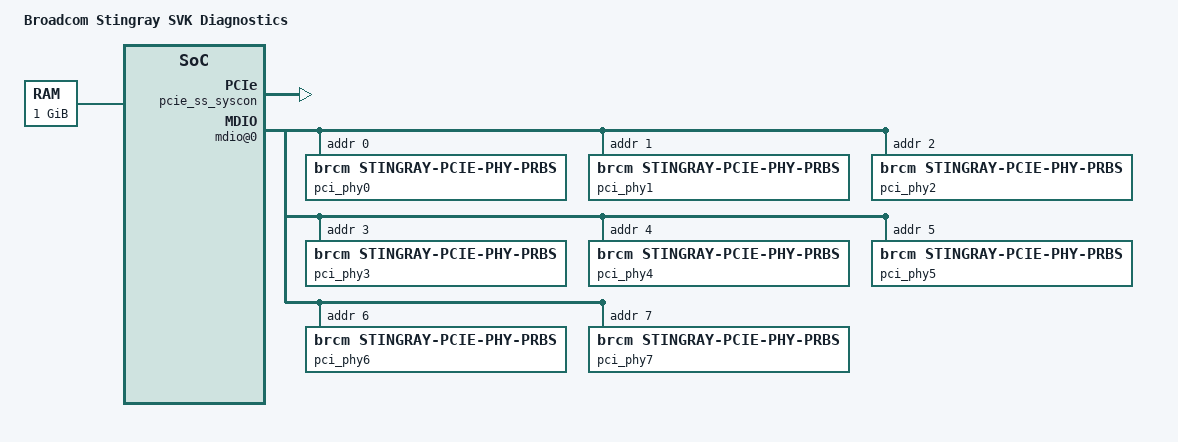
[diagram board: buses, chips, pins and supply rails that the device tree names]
/*
 *  BSD LICENSE
 *
 *  Copyright(c) 2016 Broadcom.  All rights reserved.
 *
 *  Redistribution and use in source and binary forms, with or without
 *  modification, are permitted provided that the following conditions
 *  are met:
 *
 *    * Redistributions of source code must retain the above copyright
 *      notice, this list of conditions and the following disclaimer.
 *    * Redistributions in binary form must reproduce the above copyright
 *      notice, this list of conditions and the following disclaimer in
 *      the documentation and/or other materials provided with the
 *      distribution.
 *    * Neither the name of Broadcom Corporation nor the names of its
 *      contributors may be used to endorse or promote products derived
 *      from this software without specific prior written permission.
 *
 *  THIS SOFTWARE IS PROVIDED BY THE COPYRIGHT HOLDERS AND CONTRIBUTORS
 *  "AS IS" AND ANY EXPRESS OR IMPLIED WARRANTIES, INCLUDING, BUT NOT
 *  LIMITED TO, THE IMPLIED WARRANTIES OF MERCHANTABILITY AND FITNESS FOR
 *  A PARTICULAR PURPOSE ARE DISCLAIMED. IN NO EVENT SHALL THE COPYRIGHT
 *  OWNER OR CONTRIBUTORS BE LIABLE FOR ANY DIRECT, INDIRECT, INCIDENTAL,
 *  SPECIAL, EXEMPLARY, OR CONSEQUENTIAL DAMAGES (INCLUDING, BUT NOT
 *  LIMITED TO, PROCUREMENT OF SUBSTITUTE GOODS OR SERVICES; LOSS OF USE,
 *  DATA, OR PROFITS; OR BUSINESS INTERRUPTION) HOWEVER CAUSED AND ON ANY
 *  THEORY OF LIABILITY, WHETHER IN CONTRACT, STRICT LIABILITY, OR TORT
 *  (INCLUDING NEGLIGENCE OR OTHERWISE) ARISING IN ANY WAY OUT OF THE USE
 *  OF THIS SOFTWARE, EVEN IF ADVISED OF THE POSSIBILITY OF SUCH DAMAGE.
 */

/dts-v1/;

#include "stingray.dtsi"

/ {
	model = "Broadcom Stingray SVK Diagnostics";
	compatible = "brcm,stingray-svk", "brcm,stingray";

	chosen {
		bootargs = "console=ttyS0,115200n8 earlycon=uart8250, \
			    mmio32,0x66130000";
	};

	memory {
		device_type = "memory";
		reg = <0x000000000 0x80000000 0x00000000 0x40000000>;
	};

	pcie_ss_syscon: syscon@40000000 {
		compatible = "syscon";
		reg = <0x0 0x40000000 0x0 0x1000>;
	};

	hsls {
		mdio_mux_iproc: mdio-mux@6892023c {
			compatible = "brcm,mdio-mux-iproc";
			reg = <0x6892023c 0x14>;
			#address-cells = <1>;
			#size-cells = <0>;

			mdio@0 {
				reg = <0x0>;
				#address-cells = <1>;
				#size-cells = <0>;

				pci_phy0: phy@0 {
					compatible = "brcm,stingray-pcie-phy-prbs";
					reg = <0x0>;
					brcm,pcie-strap-syscon = <&pcie_ss_syscon>;
					status = "ok";
				};
				pci_phy1: phy@1 {
					compatible = "brcm,stingray-pcie-phy-prbs";
					reg = <0x1>;
					brcm,pcie-strap-syscon = <&pcie_ss_syscon>;
					status = "ok";
				};
				pci_phy2: phy@2 {
					compatible = "brcm,stingray-pcie-phy-prbs";
					reg = <0x2>;
					brcm,pcie-strap-syscon = <&pcie_ss_syscon>;
					status = "ok";
				};
				pci_phy3: phy@3 {
					compatible = "brcm,stingray-pcie-phy-prbs";
					reg = <0x3>;
					brcm,pcie-strap-syscon = <&pcie_ss_syscon>;
					status = "ok";
				};
				pci_phy4: phy@4 {
					compatible = "brcm,stingray-pcie-phy-prbs";
					reg = <0x4>;
					brcm,pcie-strap-syscon = <&pcie_ss_syscon>;
					status = "ok";
				};
				pci_phy5: phy@5 {
					compatible = "brcm,stingray-pcie-phy-prbs";
					reg = <0x5>;
					brcm,pcie-strap-syscon = <&pcie_ss_syscon>;
					status = "ok";
				};
				pci_phy6: phy@6 {
					compatible = "brcm,stingray-pcie-phy-prbs";
					reg = <0x6>;
					brcm,pcie-strap-syscon = <&pcie_ss_syscon>;
					status = "ok";
				};
				pci_phy7: phy@7 {
					compatible = "brcm,stingray-pcie-phy-prbs";
					reg = <0x7>;
					brcm,pcie-strap-syscon = <&pcie_ss_syscon>;
					status = "ok";
				};
			};
		};
	};
};
